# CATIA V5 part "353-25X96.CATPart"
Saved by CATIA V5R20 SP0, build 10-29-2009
Part number: 353-25X96
Definition: NONE
Nomenclature: 353-25X96
Source: Unknown
Description: 353-25X96
Bounding box of the stored display mesh (mm): x -7 to 89, y -19 to 19, z -19 to 19
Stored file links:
  C:\Users\Utente\Desktop\IO LAVORO\3D X SITO CF\X SITO\PLASTICA\353\353-25X96.CATPart

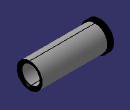
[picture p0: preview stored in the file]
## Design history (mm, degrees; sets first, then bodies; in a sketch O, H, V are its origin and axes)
Body1 "353-25X96" (main body)
  Solid1: solid without history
